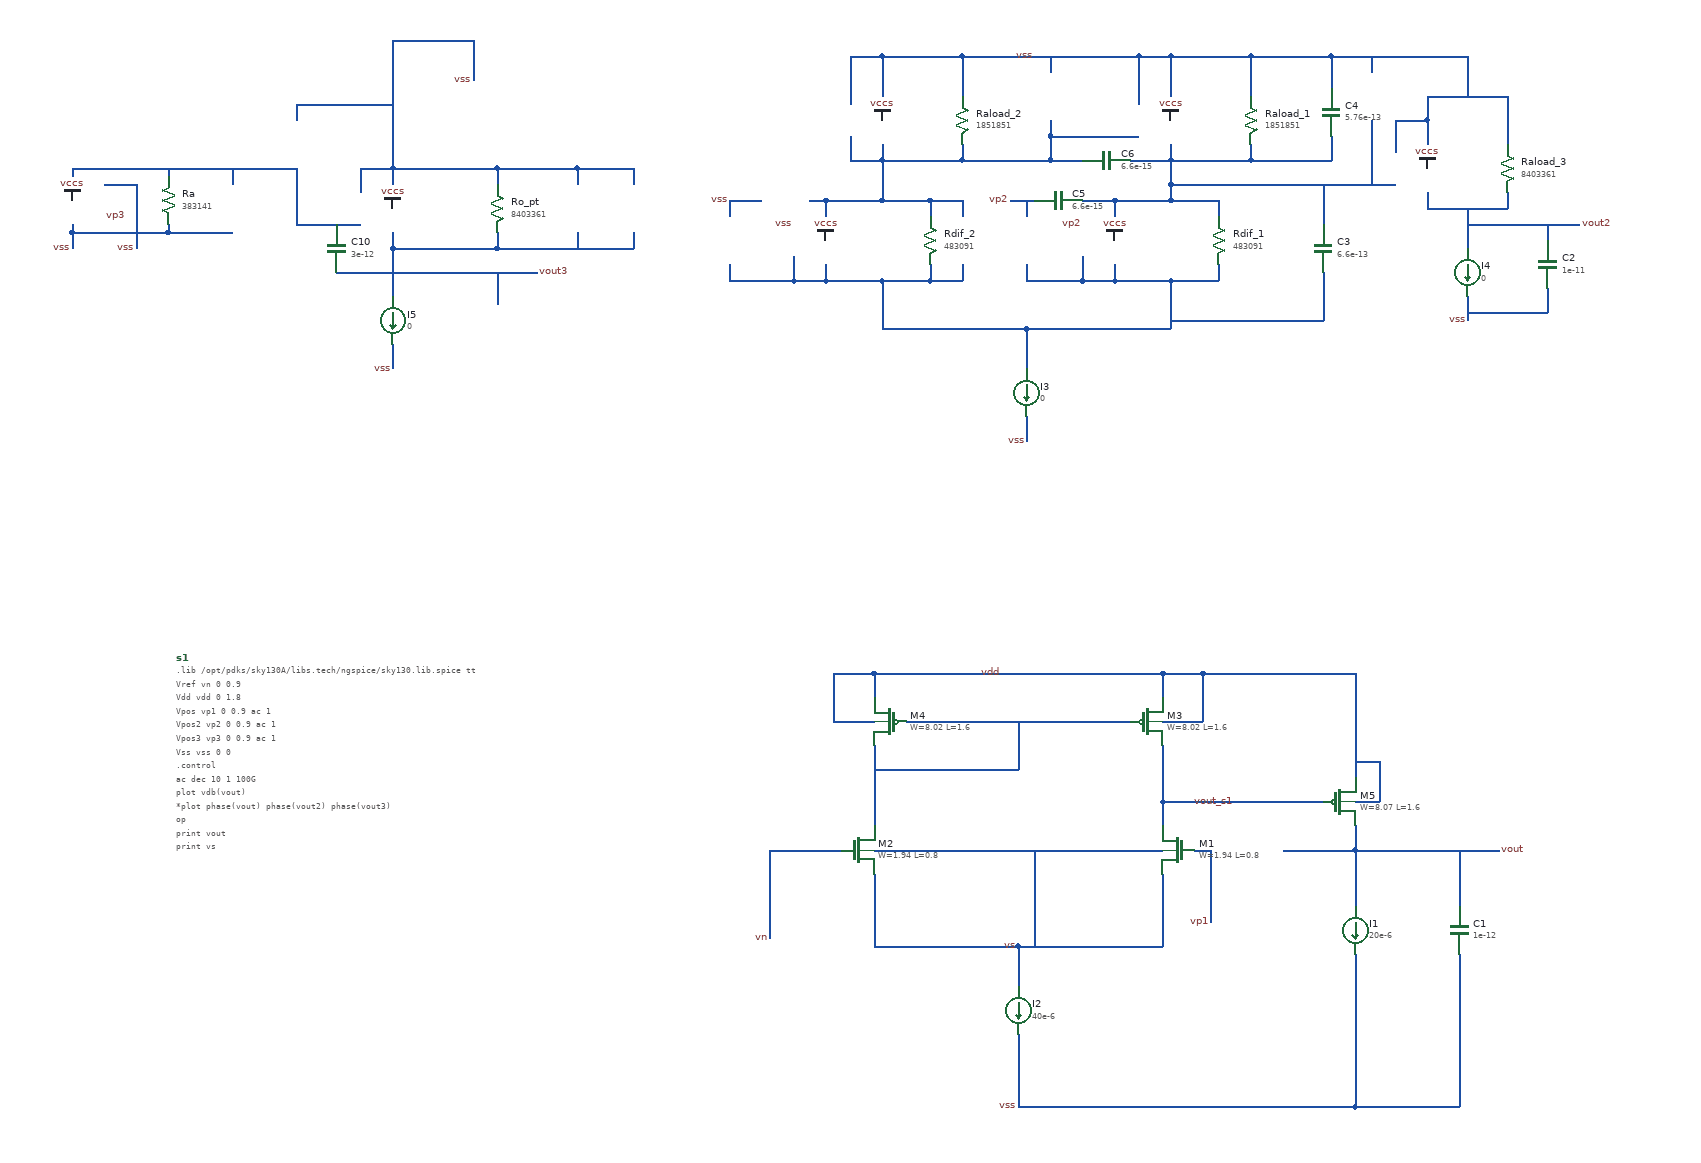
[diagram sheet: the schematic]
v {xschem version=3.4.5 file_version=1.2
}
G {}
K {}
V {}
S {}
E {}
N -220 20 -220 80 {
lab=vs}
N -40 80 140 80 {
lab=vs}
N -40 80 -40 130 {
lab=vs}
N 100 -260 140 -260 {
lab=vdd}
N -220 -130 -220 -80 {
lab=#net1}
N 140 -100 340 -100 {
lab=vout_s1}
N -350 -40 -350 -10 {
lab=vn}
N -350 50 -350 70 {
lab=vn}
N -350 -40 -260 -40 {
lab=vn}
N 200 30 200 50 {
lab=vp1}
N 200 -40 200 -30 {
lab=vp1}
N -40 190 -40 220 {
lab=vss}
N -220 80 -40 80 {
lab=vs}
N -220 -260 -120 -260 {
lab=vdd}
N 140 -130 140 -100 {
lab=vout_s1}
N -120 -260 100 -260 {
lab=vdd}
N -350 -10 -350 50 {
lab=vn}
N 200 -30 200 30 {
lab=vp1}
N 140 -160 140 -130 {
lab=vout_s1}
N -220 -170 -220 -130 {
lab=#net1}
N -220 -260 -220 -230 {
lab=vdd}
N 140 -170 140 -160 {
lab=vout_s1}
N 140 -260 140 -230 {
lab=vdd}
N 140 -100 140 -70 {
lab=vout_s1}
N 140 -10 140 80 {
lab=vs}
N -220 -80 -220 -70 {
lab=#net1}
N -220 -10 -220 20 {
lab=vs}
N 180 -40 200 -40 {
lab=vp1}
N -220 -40 140 -40 {
lab=vs}
N -20 -40 -20 80 {
lab=vs}
N -40 220 -40 280 {
lab=vss}
N -180 -200 100 -200 {
lab=#net1}
N -40 -200 -40 -140 {
lab=#net1}
N -220 -140 -40 -140 {
lab=#net1}
N -270 -200 -220 -200 {
lab=vdd}
N -270 -260 -270 -200 {
lab=vdd}
N -270 -260 -220 -260 {
lab=vdd}
N 140 -200 190 -200 {
lab=vdd}
N 190 -260 190 -200 {
lab=vdd}
N 140 -260 190 -260 {
lab=vdd}
N 380 -260 380 -130 {
lab=vdd}
N 190 -260 380 -260 {
lab=vdd}
N 380 -100 410 -100 {
lab=vdd}
N 410 -150 410 -100 {
lab=vdd}
N 380 -150 410 -150 {
lab=vdd}
N 380 -40 430 -40 {
lab=vout}
N 380 -70 380 -40 {
lab=vout}
N 380 -40 380 30 {
lab=vout}
N 380 100 380 280 {
lab=vss}
N -40 280 380 280 {
lab=vss}
N 380 90 380 100 {
lab=vss}
N 430 -40 560 -40 {
lab=vout}
N 510 -40 510 30 {
lab=vout}
N 510 90 510 280 {
lab=vss}
N 380 280 510 280 {
lab=vss}
N -280 -850 -280 -830 {
lab=#net2}
N -280 -770 -280 -750 {
lab=#net3}
N -150 -850 -150 -830 {
lab=#net2}
N -210 -850 -150 -850 {
lab=#net2}
N -150 -770 -150 -750 {
lab=#net3}
N -210 -750 -150 -750 {
lab=#net3}
N 80 -850 80 -830 {
lab=#net4}
N 80 -770 80 -750 {
lab=#net3}
N 210 -850 210 -830 {
lab=#net4}
N 150 -850 210 -850 {
lab=#net4}
N 210 -770 210 -750 {
lab=#net3}
N 150 -750 210 -750 {
lab=#net3}
N -210 -750 -210 -690 {
lab=#net3}
N -30 -690 150 -690 {
lab=#net3}
N 150 -750 150 -690 {
lab=#net3}
N -30 -690 -30 -640 {
lab=#net3}
N 150 -1030 150 -980 {
lab=vss}
N 110 -1030 150 -1030 {
lab=vss}
N -210 -900 -210 -850 {
lab=#net2}
N 150 -870 150 -850 {
lab=#net4}
N -210 -900 -110 -900 {
lab=#net2}
N 250 -1030 250 -980 {
lab=vss}
N 250 -920 250 -900 {
lab=#net4}
N 150 -900 250 -900 {
lab=#net4}
N 150 -1030 250 -1030 {
lab=vss}
N 150 -870 350 -870 {
lab=#net4}
N -320 -780 -320 -750 {
lab=#net3}
N -320 -750 -280 -750 {
lab=#net3}
N 40 -780 40 -750 {
lab=#net3}
N 40 -750 80 -750 {
lab=#net3}
N -30 -580 -30 -550 {
lab=vss}
N -250 -1030 -210 -1030 {
lab=vss}
N 110 -1030 110 -970 {
lab=vss}
N -280 -750 -210 -750 {
lab=#net3}
N 80 -750 150 -750 {
lab=#net3}
N -210 -690 -30 -690 {
lab=#net3}
N -280 -850 -210 -850 {
lab=#net2}
N 80 -850 150 -850 {
lab=#net4}
N -210 -1030 -110 -1030 {
lab=vss}
N 150 -920 150 -900 {
lab=#net4}
N 150 -900 150 -870 {
lab=#net4}
N -110 -1030 110 -1030 {
lab=vss}
N -40 -850 -20 -850 {
lab=vp2}
N 40 -850 80 -850 {
lab=#net4}
N -30 -770 -30 -750 {
lab=#net3}
N 0 -930 0 -900 {
lab=#net2}
N 0 -930 110 -930 {
lab=#net2}
N -100 -900 0 -900 {
lab=#net2}
N -110 -900 -100 -900 {
lab=#net2}
N -210 -1030 -210 -980 {
lab=vss}
N -110 -1030 -110 -980 {
lab=vss}
N -110 -920 -110 -900 {
lab=#net2}
N -250 -1030 -250 -970 {
lab=vss}
N -210 -920 -210 -900 {
lab=#net2}
N -250 -930 -250 -900 {
lab=#net2}
N -250 -900 -210 -900 {
lab=#net2}
N -30 -850 -30 -830 {
lab=vp2}
N -50 -850 -40 -850 {
lab=vp2}
N 100 -900 150 -900 {
lab=#net4}
N 0 -900 40 -900 {
lab=#net2}
N 0 -1030 0 -1010 {
lab=vss}
N 0 -950 0 -930 {
lab=#net2}
N 350 -1030 350 -990 {
lab=vss}
N 250 -1030 350 -1030 {
lab=vss}
N 350 -930 350 -900 {
lab=#net4}
N 250 -900 350 -900 {
lab=#net4}
N -300 -850 -280 -850 {
lab=#net2}
N -400 -850 -400 -830 {
lab=vss}
N -400 -850 -360 -850 {
lab=vss}
N -400 -770 -400 -750 {
lab=#net3}
N -400 -750 -320 -750 {
lab=#net3}
N -110 -850 -110 -830 {
lab=#net2}
N -150 -850 -110 -850 {
lab=#net2}
N -110 -770 -110 -750 {
lab=#net3}
N -150 -750 -110 -750 {
lab=#net3}
N -30 -750 10 -750 {
lab=#net3}
N 10 -750 40 -750 {
lab=#net3}
N 570 -860 570 -840 {
lab=vout2}
N 470 -840 570 -840 {
lab=vout2}
N 470 -860 470 -840 {
lab=vout2}
N 350 -870 380 -870 {
lab=#net4}
N 380 -870 430 -870 {
lab=#net4}
N 430 -950 430 -910 {
lab=vss}
N 430 -950 470 -950 {
lab=vss}
N 470 -950 470 -920 {
lab=vss}
N 570 -980 570 -920 {
lab=vss}
N 470 -980 570 -980 {
lab=vss}
N 470 -980 470 -950 {
lab=vss}
N 520 -1030 520 -980 {
lab=vss}
N 350 -1030 520 -1030 {
lab=vss}
N 520 -840 520 -790 {
lab=vout2}
N 520 -730 520 -700 {
lab=vss}
N 520 -820 660 -820 {
lab=vout2}
N 620 -820 620 -800 {
lab=vout2}
N 620 -740 620 -710 {
lab=vss}
N 520 -710 620 -710 {
lab=vss}
N 340 -870 340 -820 {
lab=#net4}
N 340 -760 340 -700 {
lab=#net3}
N 320 -700 340 -700 {
lab=#net3}
N 150 -700 320 -700 {
lab=#net3}
N 400 -1030 400 -1010 {
lab=vss}
N 400 -950 400 -870 {
lab=#net4}
N -820 -890 -820 -870 {
lab=vss}
N -820 -810 -820 -790 {
lab=vout3}
N -690 -890 -690 -880 {
lab=vss}
N -820 -890 -690 -890 {
lab=vss}
N -690 -880 -690 -870 {
lab=vss}
N -690 -810 -690 -790 {
lab=vout3}
N -820 -790 -690 -790 {
lab=vout3}
N -850 -890 -820 -890 {
lab=vss}
N -860 -890 -850 -890 {
lab=vss}
N -940 -890 -940 -860 {
lab=#net5}
N -820 -790 -820 -740 {
lab=vout3}
N -820 -660 -820 -640 {
lab=vss}
N -820 -1020 -820 -890 {
lab=vss}
N -1060 -890 -960 -890 {
lab=#net5}
N -1220 -890 -1170 -890 {
lab=#net5}
N -1170 -890 -1140 -890 {
lab=#net5}
N -1140 -890 -1110 -890 {
lab=#net5}
N -1220 -820 -1220 -810 {
lab=vss}
N -1220 -810 -1220 -790 {
lab=vss}
N -1220 -810 -1100 -810 {
lab=vss}
N -1100 -820 -1100 -810 {
lab=vss}
N -1100 -890 -1100 -880 {
lab=#net5}
N -820 -760 -650 -760 {
lab=vout3}
N -1220 -890 -1220 -880 {
lab=#net5}
N -1110 -890 -1060 -890 {
lab=#net5}
N -650 -760 -640 -760 {
lab=vout3}
N -940 -820 -860 -820 {
lab=#net5}
N -940 -860 -940 -820 {
lab=#net5}
N -860 -890 -860 -860 {
lab=vss}
N -960 -890 -940 -890 {
lab=#net5}
N -720 -1050 -720 -1020 {
lab=vss}
N -820 -1050 -720 -1050 {
lab=vss}
N -820 -1050 -820 -1030 {
lab=vss}
N -820 -1030 -820 -1020 {
lab=vss}
N -720 -1010 -720 -1000 {
lab=vss}
N -720 -1020 -720 -1010 {
lab=vss}
N -1140 -870 -1140 -830 {
lab=vss}
N -1180 -870 -1140 -870 {
lab=vss}
N -820 -740 -820 -730 {
lab=vout3}
N -820 -670 -820 -660 {
lab=vss}
N -1140 -830 -1140 -790 {
lab=vss}
N -1020 -890 -1020 -880 {
lab=#net5}
N -1020 -880 -1020 -870 {
lab=#net5}
N -1070 -810 -1020 -810 {
lab=vss}
N -1100 -810 -1070 -810 {
lab=vss}
N -690 -760 -690 -720 {
lab=vout3}
N -940 -970 -940 -950 {
lab=vss}
N -940 -970 -820 -970 {
lab=vss}
N -590 -890 -590 -870 {
lab=vss}
N -690 -890 -590 -890 {
lab=vss}
N -590 -810 -590 -790 {
lab=vout3}
N -690 -790 -590 -790 {
lab=vout3}
N -890 -760 -820 -760 {
lab=vout3}
N -520 -890 -520 -870 {
lab=vss}
N -590 -890 -520 -890 {
lab=vss}
N -520 -810 -520 -790 {
lab=vout3}
N -600 -790 -520 -790 {
lab=vout3}
N 300 -40 380 -40 {
lab=vout}
N 290 -40 300 -40 {
lab=vout}
C {devices/isource.sym} -40 160 0 0 {name=I2 value=40e-6}
C {devices/lab_pin.sym} -40 80 1 0 {name=p1 sig_type=std_logic lab=vs}
C {devices/lab_pin.sym} 560 -40 2 0 {name=p4 sig_type=std_logic lab=vout}
C {devices/lab_pin.sym} -60 -260 1 0 {name=p6 sig_type=std_logic lab=vdd}
C {devices/lab_pin.sym} -350 70 3 0 {name=p7 sig_type=std_logic lab=vn}
C {devices/lab_pin.sym} 200 50 3 0 {name=p8 sig_type=std_logic lab=vp1}
C {devices/lab_pin.sym} -40 280 3 0 {name=p9 sig_type=std_logic lab=vss}
C {sky130_fd_pr/nfet_01v8_lvt.sym} 160 -40 0 1 {name=M1
W=1.94
L=0.8
nf=1
mult=1
ad="'int((nf+1)/2) * W/nf * 0.29'" 
pd="'2*int((nf+1)/2) * (W/nf + 0.29)'"
as="'int((nf+2)/2) * W/nf * 0.29'" 
ps="'2*int((nf+2)/2) * (W/nf + 0.29)'"
nrd="'0.29 / W'" nrs="'0.29 / W'"
sa=0 sb=0 sd=0
model=nfet_01v8_lvt
spiceprefix=X}
C {sky130_fd_pr/nfet_01v8_lvt.sym} -240 -40 0 0 {name=M2
W=1.94
L=0.8
nf=1
mult=1
ad="'int((nf+1)/2) * W/nf * 0.29'" 
pd="'2*int((nf+1)/2) * (W/nf + 0.29)'"
as="'int((nf+2)/2) * W/nf * 0.29'" 
ps="'2*int((nf+2)/2) * (W/nf + 0.29)'"
nrd="'0.29 / W'" nrs="'0.29 / W'"
sa=0 sb=0 sd=0
model=nfet_01v8_lvt
spiceprefix=X
}
C {sky130_fd_pr/pfet_01v8_lvt.sym} 120 -200 0 0 {name=M3
W=8.02
L=1.6
nf=1
mult=1
ad="'int((nf+1)/2) * W/nf * 0.29'" 
pd="'2*int((nf+1)/2) * (W/nf + 0.29)'"
as="'int((nf+2)/2) * W/nf * 0.29'" 
ps="'2*int((nf+2)/2) * (W/nf + 0.29)'"
nrd="'0.29 / W'" nrs="'0.29 / W'"
sa=0 sb=0 sd=0
model=pfet_01v8_lvt
spiceprefix=X
}
C {sky130_fd_pr/pfet_01v8_lvt.sym} -200 -200 0 1 {name=M4
W=8.02
L=1.6
nf=1
mult=1
ad="'int((nf+1)/2) * W/nf * 0.29'" 
pd="'2*int((nf+1)/2) * (W/nf + 0.29)'"
as="'int((nf+2)/2) * W/nf * 0.29'" 
ps="'2*int((nf+2)/2) * (W/nf + 0.29)'"
nrd="'0.29 / W'" nrs="'0.29 / W'"
sa=0 sb=0 sd=0
model=pfet_01v8_lvt
spiceprefix=X
}
C {sky130_fd_pr/pfet_01v8_lvt.sym} 360 -100 0 0 {name=M5
W=8.07
L=1.6
nf=1
mult=1
ad="'int((nf+1)/2) * W/nf * 0.29'" 
pd="'2*int((nf+1)/2) * (W/nf + 0.29)'"
as="'int((nf+2)/2) * W/nf * 0.29'" 
ps="'2*int((nf+2)/2) * (W/nf + 0.29)'"
nrd="'0.29 / W'" nrs="'0.29 / W'"
sa=0 sb=0 sd=0
model=pfet_01v8_lvt
spiceprefix=X
}
C {devices/isource.sym} 380 60 0 0 {name=I1 value=20e-6}
C {devices/code_shown.sym} -1090 -280 0 0 {name=s1 only_toplevel=false value="

.lib /opt/pdks/sky130A/libs.tech/ngspice/sky130.lib.spice tt

Vref vn 0 0.9
Vdd vdd 0 1.8
Vpos vp1 0 0.9 ac 1
Vpos2 vp2 0 0.9 ac 1
Vpos3 vp3 0 0.9 ac 1
Vss vss 0 0

.control
ac dec 10 1 100G
plot vdb(vout)
*plot phase(vout) phase(vout2) phase(vout3)
op
print vout
print vs
print vout_s1
.endc

*.control
*tran 10n 1u
*plot vout vs
*.endc

"}
C {devices/res.sym} -150 -800 0 0 {name=Rdif_2
value=483091
footprint=1206
device=resistor
m=1}
C {devices/res.sym} 210 -800 0 0 {name=Rdif_1
value=483091
footprint=1206
device=resistor
m=1}
C {devices/isource.sym} -30 -610 0 0 {name=I3 value=0}
C {devices/lab_pin.sym} -50 -850 0 0 {name=p5 sig_type=std_logic lab=vp2}
C {devices/lab_pin.sym} 660 -820 2 0 {name=p10 sig_type=std_logic lab=vout2}
C {devices/lab_pin.sym} -30 -550 3 0 {name=p12 sig_type=std_logic lab=vss}
C {devices/lab_pin.sym} 40 -820 0 0 {name=p13 sig_type=std_logic lab=vp2}
C {devices/lab_pin.sym} -20 -1030 1 0 {name=p3 sig_type=std_logic lab=vss}
C {devices/lab_pin.sym} -320 -820 0 0 {name=p11 sig_type=std_logic lab=vss}
C {devices/vccs.sym} 80 -800 0 0 {name=Gdif_1 value=0.000405}
C {devices/vccs.sym} -280 -800 0 0 {name=Gdif_2 value=0.000405}
C {devices/vccs.sym} 150 -950 2 1 {name=Gaload value=0.0002234}
C {devices/vccs.sym} -210 -950 2 1 {name=Gaload1 value=0.0002234}
C {devices/res.sym} 250 -950 0 0 {name=Raload_1
value=1851851
footprint=1206
device=resistor
m=1}
C {devices/res.sym} -110 -950 0 0 {name=Raload_2
value=1851851
footprint=1206
device=resistor
m=1}
C {devices/lab_pin.sym} -400 -850 0 0 {name=p2 sig_type=std_logic lab=vss}
C {devices/vccs.sym} 470 -890 2 1 {name=Gaload2 value=0.000154}
C {devices/res.sym} 570 -890 0 0 {name=Raload_3
value=8403361
footprint=1206
device=resistor
m=1}
C {devices/isource.sym} 520 -760 0 0 {name=I4 value=0}
C {devices/lab_pin.sym} 520 -700 3 0 {name=p14 sig_type=std_logic lab=vss}
C {capa.sym} 620 -770 0 0 {name=C2
m=1
value=1e-11
footprint=1206
device="ceramic capacitor"}
C {capa.sym} 340 -790 2 0 {name=C3
m=1
value=6.6e-13
footprint=1206
device="ceramic capacitor"}
C {capa.sym} 350 -960 2 0 {name=C4
m=1
value=5.76e-13
footprint=1206
device="ceramic capacitor"}
C {capa.sym} 10 -850 3 0 {name=C5
m=1
value=6.6e-15
footprint=1206
device="ceramic capacitor"}
C {capa.sym} 70 -900 3 0 {name=C6
m=1
value=6.6e-15
footprint=1206
device="ceramic capacitor"}
C {devices/res.sym} -690 -840 0 0 {name=Ro_pt
value=8403361
footprint=1206
device=resistor
m=1}
C {devices/vccs.sym} -820 -840 2 1 {name=Gm_pt value=0.000154}
C {devices/vccs.sym} -1220 -850 2 0 {name=Gma value=-0.000405}
C {devices/res.sym} -1100 -850 2 0 {name=Ra
value=383141
footprint=1206
device=resistor
m=1}
C {devices/lab_pin.sym} -1180 -830 2 0 {name=p15 sig_type=std_logic lab=vp3}
C {devices/lab_pin.sym} -820 -640 3 0 {name=p17 sig_type=std_logic lab=vss}
C {devices/isource.sym} -820 -700 0 0 {name=I5 value=0}
C {devices/lab_pin.sym} -640 -760 2 0 {name=p20 sig_type=std_logic lab=vout3}
C {devices/lab_pin.sym} -1140 -790 3 0 {name=p18 sig_type=std_logic lab=vss
value=vref}
C {devices/lab_pin.sym} -720 -1000 3 0 {name=p19 sig_type=std_logic lab=vss
value=vref}
C {devices/lab_pin.sym} -1220 -790 3 0 {name=p16 sig_type=std_logic lab=vss
value=vref}
C {capa.sym} -890 -790 0 0 {name=C10
m=1
value=3e-12
footprint=1206
device="ceramic capacitor"}
C {devices/lab_pin.sym} 230 -100 1 0 {name=p21 sig_type=std_logic lab=vout_s1}
C {capa.sym} 510 60 2 0 {name=C1
m=1
value=1e-12
footprint=1206
device="ceramic capacitor"}
